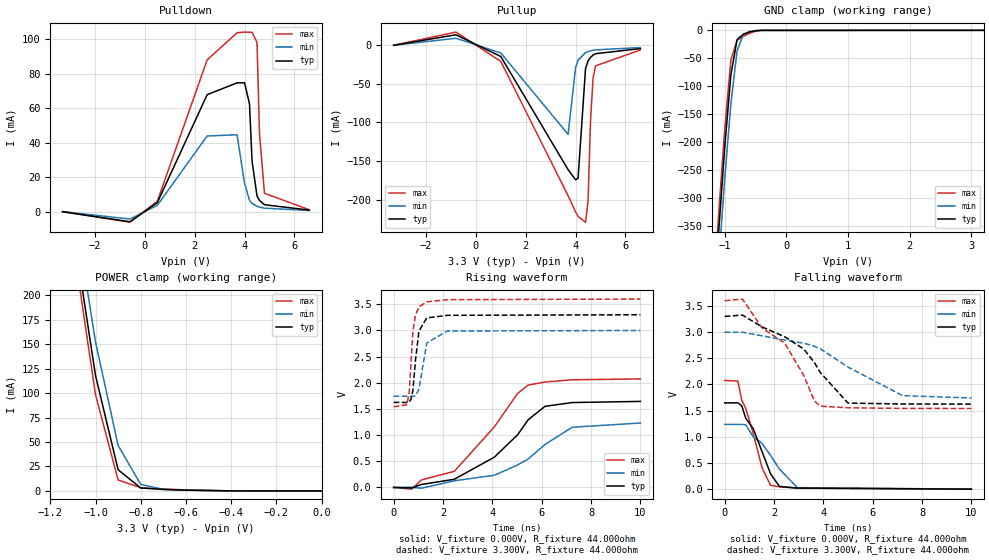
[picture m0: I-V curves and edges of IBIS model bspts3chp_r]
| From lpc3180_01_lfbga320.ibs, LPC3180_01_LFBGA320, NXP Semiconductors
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| |   Rev 0.20 IBIS Model Design Automation Generation   |
| |   N O N - S I L I C O N   C O R R E L A T E D   |
| |   This IBIS [Model] is pre-Beta tactical support   |
| |  Note: this IBIS [Model] contains clamp curves generated   |
| |   through simulation which should not be relied upon   |
| bspts3chp
|   Bidirectional Pad 3v3
|   3state Output
|   Plain Input
|   3ns Slew Rate control
|   CMOS
|   Programmable between
|   - (p1=0, p2=1) plain input
|   - (p1=0, p2=0) with Pull Up
|   - (p1=1, p2=1) with Pull Down
|   - (p1=1, p2=0) with Repeater
|   Characterized at Core 1.2V and I/O 3.3V
| Repeater Mode (p1=1, p2=0)
[Model]   bspts3chp_r | of bspts3chp
Model_type   I/O
Polarity   Non-Inverting
Enable   Active-Low
|  Reciever Thresholds
Vinl   = 0.36V
Vinh   = 0.84V
| AC Test Load Conditions
Vref   = 0
Cref   = 1.2e-11
Rref   = 1000000000
Vmeas   = 0.6
| [Process Range]   typical   min   max
| C_comp edge width   400.000ps   400.000ps   400.000ps
| C_comp Tstrobe   40.000fs   40.000fs   40.000fs
C_comp   2.385pF   2.234pF   2.564pF
[Temperature Range]   25   125   -40
[Voltage Range]   3.30V   3.00V   3.60V
[GND Clamp Reference]   0.00V   0.00V   0.00V
[Pulldown Reference]   0.00V   0.00V   0.00V
[POWER Clamp Reference]   3.30V   3.00V   3.60V
[Pullup Reference]   3.30V   3.00V   3.60V
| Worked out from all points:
|   slope of the pulldown table from 0 to 0.495 V, typ, clamps not added: 97.1 ohm
|   slope of the pullup table from 0 to 0.495 V, typ, clamps not added: 59.3 ohm
|   GND clamp passes 1 mA (typ) near -0.51 V on its own axis
|   POWER clamp passes 1 mA (typ) near -0.63 V on its own axis
|   rising waveform, V_fixture 0.000V, R_fixture 44.000ohm: 20-80 % time 2.13ns typ, 2.37ns min, 2.1ns max; typ from 0 V to 1.64 V
|   falling waveform, V_fixture 0.000V, R_fixture 44.000ohm: 20-80 % time 927ps typ, 1.23ns min, 792ps max; typ from 1.65 V to 0 V
|   rising waveform, V_fixture 3.300V, R_fixture 44.000ohm: 20-80 % time 210ps typ, 252ps min, 185ps max; typ from 1.62 V to 3.3 V
|   falling waveform, V_fixture 3.300V, R_fixture 44.000ohm: 20-80 % time 2.17ns typ, 2.52ns min, 2.04ns max; typ from 3.3 V to 1.62 V
[GND Clamp]
| ref voltage   0.00V   0.00V   0.00V
|   Voltage   I(typ)   I(min)   I(max)
-3.3V     -4.198A    -4.223A    -4.188A
-1.2V     -526mA     -577.5mA   -497.2mA
-1.1V     -363.6mA   -417.9mA   -332.6mA
-1V       -210.1mA   -266.3mA   -177.3mA
-900mV    -79.71mA   -131.5mA   -53.29mA
-800mV    -16.76mA   -37.38mA   -17.81mA
-700mV    -7.164mA   -7.263mA   -10.92mA
-600mV    -3.002mA   -2.202mA   -5.445mA
-500mV    -699uA     -571.9uA   -1.612mA
-400mV    -79uA      -96.04uA   -163.6uA
3.2V      -4.082uA   6.375uA    -21.05uA
[Power Clamp]   | Vtable = Vcc - Vpad
| ref voltage   3.30V   3.00V   3.60V
|   Voltage   I(typ)   I(min)   I(max)
-3.3V     4.52A      4.504A     4.537A
-1.1V     269.9mA    299.6mA    255.3mA
-1V       118.1mA    152.4mA    98.46mA
-900mV    21.61mA    46.52mA    11.21mA
-800mV    3.024mA    6.678mA    3.251mA
-700mV    1.526mA    1.555mA    1.973mA
-600mV    767.7uA    705.2uA    1.011mA
-400mV    58.36uA    81.92uA    64.04uA
0V        755pA      5.591nA    627.8pA
[Pulldown]
| ref voltage   0.00V   0.00V   0.00V
|   Voltage   I(typ)   I(min)   I(max)
-3.3V     -80.68uA   -69.9uA    -74.32uA
-600mV    -5.92mA    -4.329mA   -6.172mA
500mV     5.147mA    3.568mA    5.922mA
2.5V      67.8mA     43.83mA    87.99mA
3.7V      74.65mA    44.53mA    103.7mA
4V        74.69mA    16.44mA    104.1mA
4.2V      62.38mA    6.515mA    104mA
4.3V      29.48mA    4.769mA    104mA
4.5V      9.069mA    3.068mA    98.17mA
4.6V      6.413mA    2.587mA    45.14mA
4.8V      3.956mA    1.96mA     10.6mA
6.6V      844.8uA    597.5uA    1.056mA
[Pullup]   | Vtable = Vcc - Vpad
| ref voltage   3.30V   3.00V   3.60V
|   Voltage   I(typ)   I(min)   I(max)
-3.3V     39.4uA     37.84uA    38.83uA
-800mV    13.66mA    9.123mA    17.15mA
1V        -14.52mA   -9.936mA   -20.86mA
3.7V      -161.3mA   -115.5mA   -195.1mA
4V        -174.4mA   -29.02mA   -216.2mA
4.1V      -172.4mA   -19.17mA   -221.9mA
4.4V      -30.01mA   -9.422mA   -229.4mA
4.5V      -20.39mA   -8.135mA   -202.5mA
4.6V      -15.6mA    -7.195mA   -97.92mA
4.7V      -12.75mA   -6.48mA    -42.98mA
4.8V      -10.87mA   -5.92mA    -26.67mA
6.6V      -4.278mA   -2.929mA   -6.056mA
[Ramp]
R_load   = 44.000ohm
|   dV/dt(typ)   dV/dt(min)   dV/dt(max)
dV/dt_r   1.000V/2.135ns   750.585mV/2.380ns   1.259V/2.110ns
dV/dt_f   1.021V/2.185ns   768.980mV/2.460ns   1.253V/2.025ns
[Rising Waveform]  | cubic spline decimation from 2001 points
V_fixture   = 0.000V
R_fixture   = 44.000ohm
|   Time   V(typ)   V(min)   V(max)
0s        20.64nV    394.3nV    10.69nV
730ps     -10.48mV   1.46mV     -33.3mV
1.125ns   55.92mV    -15.1mV    142.7mV
2.46ns    156.3mV    126.8mV    308.4mV
4.085ns   579.6mV    232.8mV    1.159V
5.02ns    1.004V     428.4mV    1.795V
5.455ns   1.294V     544.2mV    1.957V
6.135ns   1.55V      820.6mV    2.015V
7.235ns   1.622V     1.15V      2.057V
10ns      1.644V     1.231V     2.074V
[Falling Waveform]  | cubic spline decimation from 2001 points
V_fixture   = 0.000V
R_fixture   = 44.000ohm
|   Time   V(typ)   V(min)   V(max)
0s        1.648V     1.237V     2.077V
535ps     1.649V     1.237V     2.065V
695ps     1.589V     1.238V     1.692V
850ps     1.357V     1.229V     1.552V
1.16ns    1.154V     998.7mV    1.059V
1.51ns    721.8mV    875.4mV    413.5mV
1.86ns    292.7mV    644.5mV    73.23mV
2.22ns    52.44mV    382.5mV    45.21mV
2.945ns   20.39mV    29.25mV    19.46mV
10ns      25.46uV    53.35uV    2.164mV
[Rising Waveform]  | cubic spline decimation from 2001 points
V_fixture   = 3.300V
V_fixture_min = 3.000V
V_fixture_max = 3.600V
R_fixture   = 44.000ohm
|   Time   V(typ)   V(min)   V(max)
0s        1.625V     1.743V     1.541V
535ps     1.624V     1.743V     1.581V
630ps     1.629V     1.743V     1.81V
700ps     1.684V     1.742V     2.365V
780ps     1.852V     1.74V      2.978V
885ps     2.431V     1.748V     3.293V
1.025ns   2.984V     1.875V     3.451V
1.34ns    3.24V      2.759V     3.547V
2.17ns    3.289V     2.989V     3.588V
10ns      3.3V       3V         3.6V
[Falling Waveform]  | cubic spline decimation from 2001 points
V_fixture   = 3.300V
V_fixture_min = 3.000V
V_fixture_max = 3.600V
R_fixture   = 44.000ohm
|   Time   V(typ)   V(min)   V(max)
0s        3.3V       3V         3.6V
720ps     3.326V     2.998V     3.632V
1.515ns   3.099V     2.93V      3.079V
2.435ns   2.912V     2.85V      2.789V
3.205ns   2.676V     2.789V     2.172V
3.635ns   2.42V      2.73V      1.686V
3.87ns    2.232V     2.684V     1.586V
4.995ns   1.645V     2.334V     1.555V
7.215ns   1.627V     1.786V     1.543V
10ns      1.625V     1.743V     1.541V
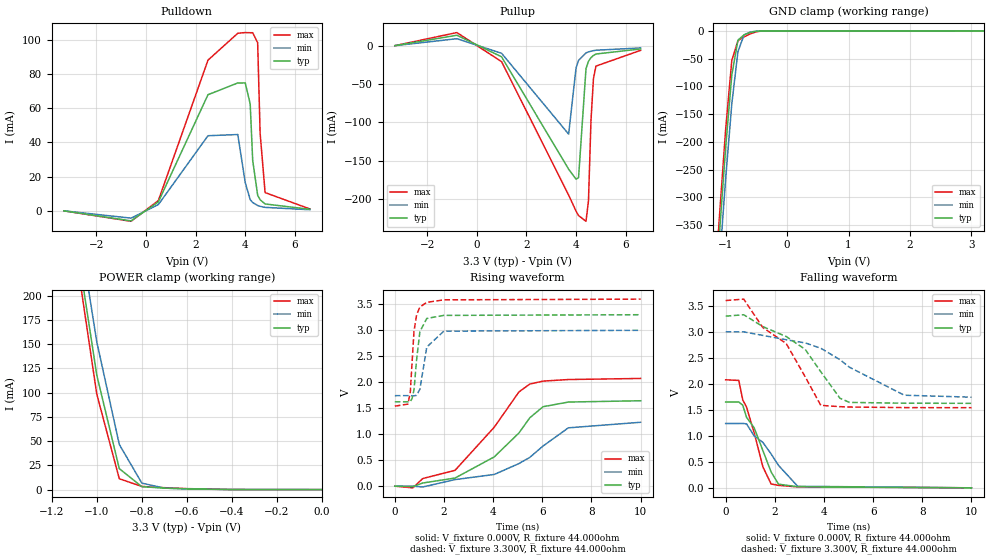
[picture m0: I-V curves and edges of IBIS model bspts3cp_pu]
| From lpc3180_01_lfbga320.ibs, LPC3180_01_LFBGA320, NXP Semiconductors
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| |   Rev 0.20 IBIS Model Design Automation Generation   |
| |   N O N - S I L I C O N   C O R R E L A T E D   |
| |   This IBIS [Model] is pre-Beta tactical support   |
| |  Note: this IBIS [Model] contains clamp curves generated   |
| |   through simulation which should not be relied upon   |
| bspts3cp
|   Bidirectional Pad 3v3
|   3state Output
|   Plain Input
|   3ns Slew Rate control
|   CMOS
|   Programmable between
|   - (p1=0, p2=1) plain input
|   - (p1=0, p2=0) with Pull Up
|   - (p1=1, p2=1) with Pull Down
|   - (p1=1, p2=0) with Repeater
|   Characterized at Core 1.2V and I/O 3.3V
| Pull Up Mode (p1=0, p2=0)
[Model]   bspts3cp_pu | of bspts3cp
Model_type   I/O
Polarity   Non-Inverting
Enable   Active-Low
|  Reciever Thresholds
Vinl   = 0.36V
Vinh   = 0.84V
| AC Test Load Conditions
Vref   = 0
Cref   = 1.2e-11
Rref   = 1000000000
Vmeas   = 0.6
| [Process Range]   typical   min   max
| C_comp edge width   400.000ps   400.000ps   400.000ps
| C_comp Tstrobe   40.000fs   40.000fs   40.000fs
C_comp   2.390pF   2.243pF   2.567pF
[Temperature Range]   25   125   -40
[Voltage Range]   3.30V   3.00V   3.60V
[GND Clamp Reference]   0.00V   0.00V   0.00V
[Pulldown Reference]   0.00V   0.00V   0.00V
[POWER Clamp Reference]   3.30V   3.00V   3.60V
[Pullup Reference]   3.30V   3.00V   3.60V
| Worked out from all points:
|   slope of the pulldown table from 0 to 0.495 V, typ, clamps not added: 97.1 ohm
|   slope of the pullup table from 0 to 0.495 V, typ, clamps not added: 59.3 ohm
|   GND clamp passes 1 mA (typ) near -0.51 V on its own axis
|   POWER clamp passes 1 mA (typ) near -0.63 V on its own axis
|   rising waveform, V_fixture 0.000V, R_fixture 44.000ohm: 20-80 % time 2.13ns typ, 2.37ns min, 2.1ns max; typ from 0.001 V to 1.65 V
|   falling waveform, V_fixture 0.000V, R_fixture 44.000ohm: 20-80 % time 929ps typ, 1.23ns min, 791ps max; typ from 1.65 V to 0.001 V
|   rising waveform, V_fixture 3.300V, R_fixture 44.000ohm: 20-80 % time 210ps typ, 253ps min, 184ps max; typ from 1.62 V to 3.3 V
|   falling waveform, V_fixture 3.300V, R_fixture 44.000ohm: 20-80 % time 2.17ns typ, 2.52ns min, 2.04ns max; typ from 3.3 V to 1.62 V
[GND Clamp]
| ref voltage   0.00V   0.00V   0.00V
|   Voltage   I(typ)   I(min)   I(max)
-3.3V     -4.198A    -4.223A    -4.188A
-1.2V     -526mA     -577.5mA   -497.2mA
-1.1V     -363.6mA   -417.9mA   -332.6mA
-1V       -210.1mA   -266.3mA   -177.3mA
-900mV    -79.72mA   -131.5mA   -53.31mA
-800mV    -16.78mA   -37.39mA   -17.84mA
-700mV    -7.182mA   -7.273mA   -10.95mA
-600mV    -3.024mA   -2.214mA   -5.482mA
-500mV    -725.7uA   -585.9uA   -1.656mA
-400mV    -110.5uA   -112.8uA   -213.4uA
3.2V      -4.082uA   6.375uA    -21.05uA
[Power Clamp]   | Vtable = Vcc - Vpad
| ref voltage   3.30V   3.00V   3.60V
|   Voltage   I(typ)   I(min)   I(max)
-3.3V     4.52A      4.504A     4.537A
-1.1V     269.9mA    299.6mA    255.3mA
-1V       118.1mA    152.4mA    98.46mA
-900mV    21.61mA    46.52mA    11.21mA
-800mV    3.024mA    6.678mA    3.251mA
-700mV    1.526mA    1.555mA    1.973mA
-600mV    767.7uA    705.2uA    1.011mA
-400mV    58.36uA    81.92uA    64.04uA
0V        755.1pA    5.591nA    627.9pA
[Pulldown]
| ref voltage   0.00V   0.00V   0.00V
|   Voltage   I(typ)   I(min)   I(max)
-3.3V     -80.68uA   -69.9uA    -74.32uA
-600mV    -5.92mA    -4.329mA   -6.173mA
500mV     5.147mA    3.568mA    5.923mA
2.5V      67.8mA     43.83mA    87.99mA
3.7V      74.65mA    44.53mA    103.7mA
4V        74.69mA    16.44mA    104.1mA
4.2V      62.38mA    6.515mA    104mA
4.3V      29.48mA    4.769mA    104mA
4.5V      9.069mA    3.068mA    98.17mA
4.6V      6.413mA    2.587mA    45.14mA
4.8V      3.956mA    1.96mA     10.6mA
6.6V      844.8uA    597.5uA    1.056mA
[Pullup]   | Vtable = Vcc - Vpad
| ref voltage   3.30V   3.00V   3.60V
|   Voltage   I(typ)   I(min)   I(max)
-3.3V     39.4uA     37.84uA    38.83uA
-800mV    13.66mA    9.123mA    17.15mA
1V        -14.52mA   -9.936mA   -20.86mA
3.7V      -161.3mA   -115.5mA   -195.1mA
4V        -174.4mA   -29.02mA   -216.2mA
4.1V      -172.4mA   -19.17mA   -221.9mA
4.4V      -30.01mA   -9.422mA   -229.4mA
4.5V      -20.4mA    -8.135mA   -202.5mA
4.6V      -15.61mA   -7.195mA   -97.93mA
4.7V      -12.75mA   -6.481mA   -42.99mA
4.8V      -10.87mA   -5.92mA    -26.67mA
6.6V      -4.278mA   -2.929mA   -6.056mA
[Ramp]
R_load   = 44.000ohm
|   dV/dt(typ)   dV/dt(min)   dV/dt(max)
dV/dt_r   999.916mV/2.125ns   750.525mV/2.375ns   1.258V/2.100ns
dV/dt_f   1.021V/2.185ns   768.980mV/2.465ns   1.253V/2.025ns
[Rising Waveform]  | cubic spline decimation from 2001 points
V_fixture   = 0.000V
R_fixture   = 44.000ohm
|   Time   V(typ)   V(min)   V(max)
0s        1.464mV    895.4uV    2.142mV
730ps     -9.043mV   2.349mV    -30.93mV
1.135ns   62.23mV    -14.58mV   147.9mV
2.45ns    158mV      128.1mV    306.3mV
4.045ns   564.9mV    226.8mV    1.136V
5.05ns    1.025V     436.5mV    1.815V
5.49ns    1.317V     555mV      1.966V
6.03ns    1.53V      773.9mV    2.023V
7.06ns    1.62V      1.124V     2.053V
10ns      1.645V     1.231V     2.074V
[Falling Waveform]  | cubic spline decimation from 2001 points
V_fixture   = 0.000V
R_fixture   = 44.000ohm
|   Time   V(typ)   V(min)   V(max)
0s        1.65V      1.238V     2.077V
535ps     1.65V      1.238V     2.065V
695ps     1.59V      1.239V     1.692V
850ps     1.357V     1.23V      1.552V
1.16ns    1.156V     999.3mV    1.059V
1.515ns   717.2mV    873.5mV    404.4mV
1.85ns    304.8mV    652.5mV    74.94mV
2.15ns    71.99mV    433.1mV    48.34mV
2.93ns    22.34mV    31.53mV    19.78mV
10ns      1.49mV     948.5uV    2.164mV
[Rising Waveform]  | cubic spline decimation from 2001 points
V_fixture   = 3.300V
V_fixture_min = 3.000V
V_fixture_max = 3.600V
R_fixture   = 44.000ohm
|   Time   V(typ)   V(min)   V(max)
0s        1.625V     1.743V     1.541V
535ps     1.624V     1.743V     1.581V
630ps     1.629V     1.743V     1.811V
700ps     1.684V     1.742V     2.367V
780ps     1.853V     1.74V      2.979V
885ps     2.432V     1.749V     3.294V
1.02ns    2.974V     1.867V     3.448V
1.3ns     3.228V     2.678V     3.538V
1.995ns   3.287V     2.984V     3.586V
10ns      3.3V       3V         3.6V
[Falling Waveform]  | cubic spline decimation from 2001 points
V_fixture   = 3.300V
V_fixture_min = 3.000V
V_fixture_max = 3.600V
R_fixture   = 44.000ohm
|   Time   V(typ)   V(min)   V(max)
0s        3.3V       3V         3.6V
735ps     3.327V     2.998V     3.627V
1.515ns   3.099V     2.93V      3.079V
2.465ns   2.908V     2.847V     2.774V
3.235ns   2.662V     2.786V     2.135V
3.87ns    2.232V     2.684V     1.586V
4.65ns    1.723V     2.463V     1.561V
5.035ns   1.643V     2.319V     1.554V
7.265ns   1.627V     1.781V     1.543V
10ns      1.625V     1.743V     1.541V
